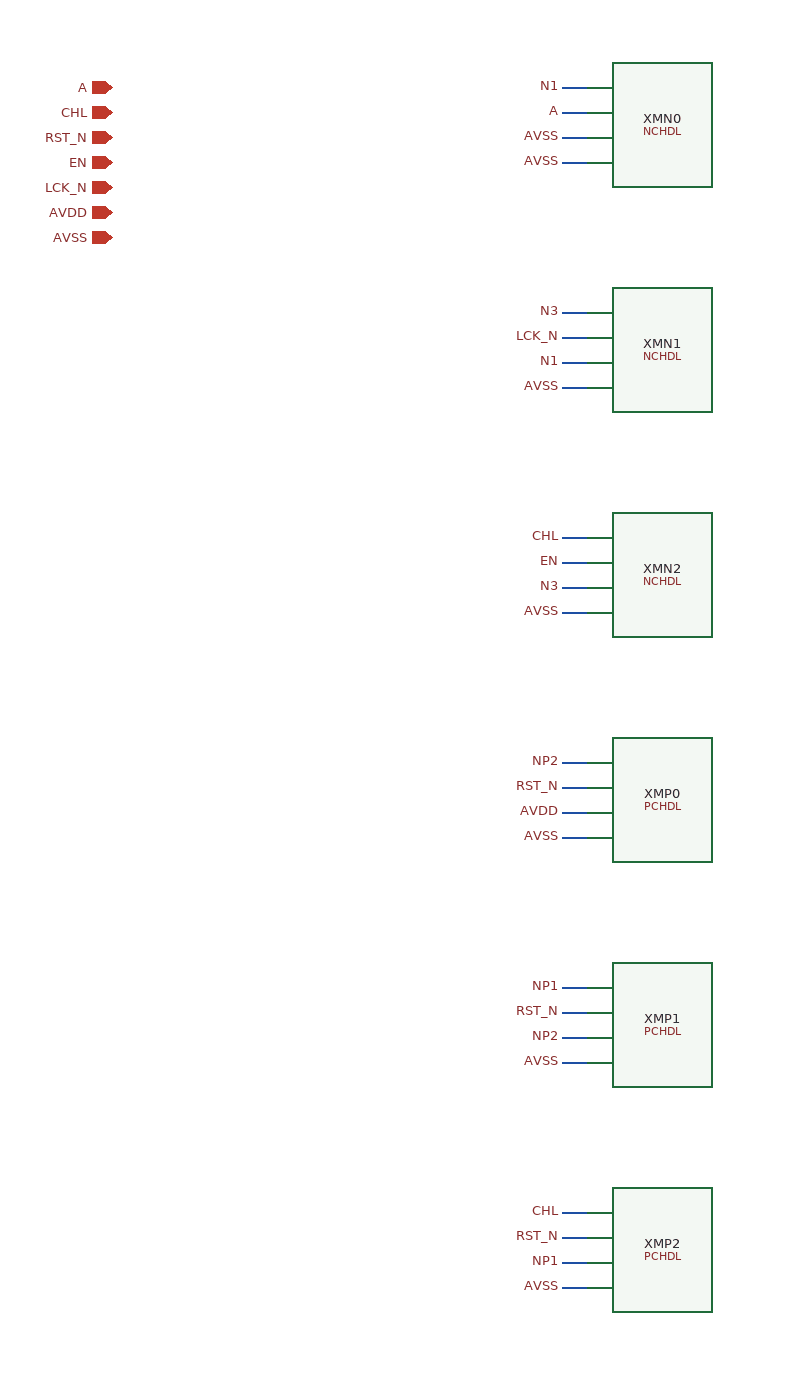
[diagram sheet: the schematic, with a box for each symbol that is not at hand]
v {xschem version=3.0.0 file_version=1.2 }
G {}
K {}
V {}
S {}
E {}
C {devices/iopin.sym} 0 0 0 0 {name=p0 lab=A}
C {devices/iopin.sym} 0 20 0 0 {name=p1 lab=CHL}
C {devices/iopin.sym} 0 40 0 0 {name=p2 lab=RST_N}
C {devices/iopin.sym} 0 60 0 0 {name=p3 lab=EN}
C {devices/iopin.sym} 0 80 0 0 {name=p4 lab=LCK_N}
C {devices/iopin.sym} 0 100 0 0 {name=p5 lab=AVDD}
C {devices/iopin.sym} 0 120 0 0 {name=p6 lab=AVSS}
C {SAR9B/NCHDL.sym} 400 0 0 0 {name=XMN0}
N 360.0 0.0 380.0 0.0 {lab=N1}
C {devices/lab_pin.sym} 360.0 0.0 0 0 {name=l0 sig_type=std_logic lab=N1 }
N 360.0 20.0 380.0 20.0 {lab=A}
C {devices/lab_pin.sym} 360.0 20.0 0 0 {name=l1 sig_type=std_logic lab=A }
N 360.0 40.0 380.0 40.0 {lab=AVSS}
C {devices/lab_pin.sym} 360.0 40.0 0 0 {name=l2 sig_type=std_logic lab=AVSS }
N 360.0 60.0 380.0 60.0 {lab=AVSS}
C {devices/lab_pin.sym} 360.0 60.0 0 0 {name=l3 sig_type=std_logic lab=AVSS }
C {SAR9B/NCHDL.sym} 400 180.0 0 0 {name=XMN1}
N 360.0 180.0 380.0 180.0 {lab=N3}
C {devices/lab_pin.sym} 360.0 180.0 0 0 {name=l4 sig_type=std_logic lab=N3 }
N 360.0 200.0 380.0 200.0 {lab=LCK_N}
C {devices/lab_pin.sym} 360.0 200.0 0 0 {name=l5 sig_type=std_logic lab=LCK_N }
N 360.0 220.0 380.0 220.0 {lab=N1}
C {devices/lab_pin.sym} 360.0 220.0 0 0 {name=l6 sig_type=std_logic lab=N1 }
N 360.0 240.0 380.0 240.0 {lab=AVSS}
C {devices/lab_pin.sym} 360.0 240.0 0 0 {name=l7 sig_type=std_logic lab=AVSS }
C {SAR9B/NCHDL.sym} 400 360.0 0 0 {name=XMN2}
N 360.0 360.0 380.0 360.0 {lab=CHL}
C {devices/lab_pin.sym} 360.0 360.0 0 0 {name=l8 sig_type=std_logic lab=CHL }
N 360.0 380.0 380.0 380.0 {lab=EN}
C {devices/lab_pin.sym} 360.0 380.0 0 0 {name=l9 sig_type=std_logic lab=EN }
N 360.0 400.0 380.0 400.0 {lab=N3}
C {devices/lab_pin.sym} 360.0 400.0 0 0 {name=l10 sig_type=std_logic lab=N3 }
N 360.0 420.0 380.0 420.0 {lab=AVSS}
C {devices/lab_pin.sym} 360.0 420.0 0 0 {name=l11 sig_type=std_logic lab=AVSS }
C {SAR9B/PCHDL.sym} 400 540.0 0 0 {name=XMP0}
N 360.0 540.0 380.0 540.0 {lab=NP2}
C {devices/lab_pin.sym} 360.0 540.0 0 0 {name=l12 sig_type=std_logic lab=NP2 }
N 360.0 560.0 380.0 560.0 {lab=RST_N}
C {devices/lab_pin.sym} 360.0 560.0 0 0 {name=l13 sig_type=std_logic lab=RST_N }
N 360.0 580.0 380.0 580.0 {lab=AVDD}
C {devices/lab_pin.sym} 360.0 580.0 0 0 {name=l14 sig_type=std_logic lab=AVDD }
N 360.0 600.0 380.0 600.0 {lab=AVSS}
C {devices/lab_pin.sym} 360.0 600.0 0 0 {name=l15 sig_type=std_logic lab=AVSS }
C {SAR9B/PCHDL.sym} 400 720.0 0 0 {name=XMP1}
N 360.0 720.0 380.0 720.0 {lab=NP1}
C {devices/lab_pin.sym} 360.0 720.0 0 0 {name=l16 sig_type=std_logic lab=NP1 }
N 360.0 740.0 380.0 740.0 {lab=RST_N}
C {devices/lab_pin.sym} 360.0 740.0 0 0 {name=l17 sig_type=std_logic lab=RST_N }
N 360.0 760.0 380.0 760.0 {lab=NP2}
C {devices/lab_pin.sym} 360.0 760.0 0 0 {name=l18 sig_type=std_logic lab=NP2 }
N 360.0 780.0 380.0 780.0 {lab=AVSS}
C {devices/lab_pin.sym} 360.0 780.0 0 0 {name=l19 sig_type=std_logic lab=AVSS }
C {SAR9B/PCHDL.sym} 400 900.0 0 0 {name=XMP2}
N 360.0 900.0 380.0 900.0 {lab=CHL}
C {devices/lab_pin.sym} 360.0 900.0 0 0 {name=l20 sig_type=std_logic lab=CHL }
N 360.0 920.0 380.0 920.0 {lab=RST_N}
C {devices/lab_pin.sym} 360.0 920.0 0 0 {name=l21 sig_type=std_logic lab=RST_N }
N 360.0 940.0 380.0 940.0 {lab=NP1}
C {devices/lab_pin.sym} 360.0 940.0 0 0 {name=l22 sig_type=std_logic lab=NP1 }
N 360.0 960.0 380.0 960.0 {lab=AVSS}
C {devices/lab_pin.sym} 360.0 960.0 0 0 {name=l23 sig_type=std_logic lab=AVSS }
